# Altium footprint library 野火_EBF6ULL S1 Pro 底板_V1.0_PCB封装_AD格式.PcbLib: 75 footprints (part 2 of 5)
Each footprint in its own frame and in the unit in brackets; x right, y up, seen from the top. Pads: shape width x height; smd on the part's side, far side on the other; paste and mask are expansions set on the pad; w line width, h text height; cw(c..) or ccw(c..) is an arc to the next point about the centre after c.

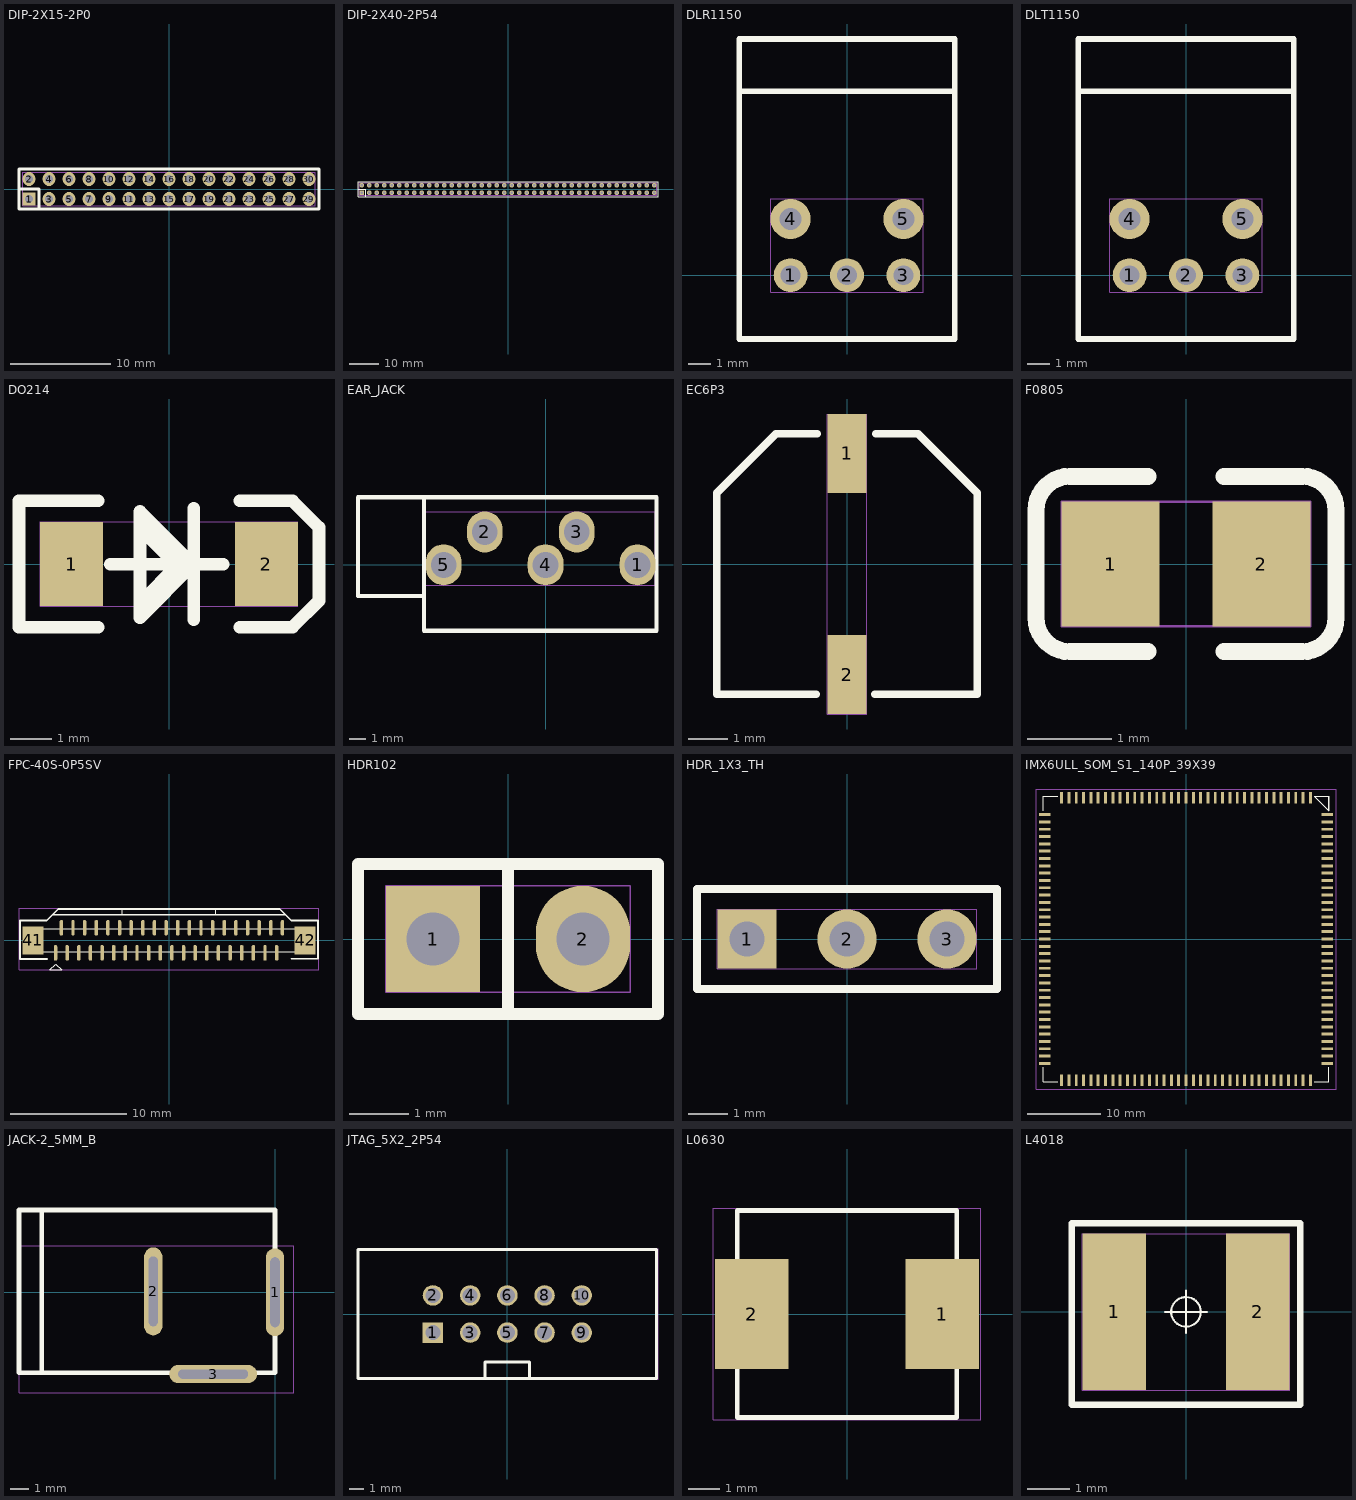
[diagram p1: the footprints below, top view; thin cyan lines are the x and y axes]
## DIP-2X15-2P0 [mil]
pads (30):
  rect 50x50 hole 32 mask+2: 1(-551.18,-39.37)
  oval 50x55 hole 32 mask+2: 2(-551.18,39.37) 3(-472.44,-39.37) 4(-472.44,39.37) 5(-393.7,-39.37) 6(-393.7,39.37) 7(-314.96,-39.37) 8(-314.96,39.37) 9(-236.22,-39.37) 10(-236.22,39.37) 11(-157.48,-39.37) 12(-157.48,39.37) 13(-78.74,-39.37) 14(-78.74,39.37) 15(0,-39.37) 16(0,39.37) 17(78.74,-39.37) 18(78.74,39.37) 19(157.48,-39.37) 20(157.48,39.37) 21(236.22,-39.37) 22(236.22,39.37) 23(314.96,-39.37) 24(314.96,39.37) 25(393.7,-39.37) 26(393.7,39.37) 27(472.44,-39.37) 28(472.44,39.37) 29(551.18,-39.37) 30(551.18,39.37)
Top Overlay:
  lines w10: -590.55,0 -511.81,0 -511.81,-78.74 ; -590.55,-78.74 590.55,-78.74 590.55,78.74 -590.55,78.74 -590.55,-78.74
Top Assembly:
  text "J38" at 57.25,25 h50
Mechanical 20:
  lines w1: -576.18,-66.87 576.18,-66.87 576.18,66.87 -576.18,66.87 -576.18,-66.87

## DIP-2X40-2P54 [mil]
pads (80):
  rect 62.99x62.99 hole 35.43 mask+2: 1(-1950,-50)
  round 62.99 hole 35.43 mask+2: 2(-1950,50) 3(-1850,-50) 4(-1850,50) 5(-1750,-50) 6(-1750,50) 7(-1650,-50) 8(-1650,50) 9(-1550,-50) 10(-1550,50) 11(-1450,-50) 12(-1450,50) 13(-1350,-50) 14(-1350,50) 15(-1250,-50) 16(-1250,50) 17(-1150,-50) 18(-1150,50) 19(-1050,-50) 20(-1050,50) 21(-950,-50) 22(-950,50) 23(-850,-50) 24(-850,50) 25(-750,-50) 26(-750,50) 27(-650,-50) 28(-650,50) 29(-550,-50) 30(-550,50) 31(-450,-50) 32(-450,50) 33(-350,-50) 34(-350,50) 35(-250,-50) 36(-250,50) 37(-150,-50) 38(-150,50) 39(-50,-50) 40(-50,50) 41(50,-50) 42(50,50) 43(150,-50) 44(150,50) 45(250,-50) 46(250,50) 47(350,-50) 48(350,50) 49(450,-50) 50(450,50) 51(550,-50) 52(550,50) 53(650,-50) 54(650,50) 55(750,-50) 56(750,50) 57(850,-50) 58(850,50) 59(950,-50) 60(950,50) 61(1050,-50) 62(1050,50) 63(1150,-50) 64(1150,50) 65(1250,-50) 66(1250,50) 67(1350,-50) 68(1350,50) 69(1450,-50) 70(1450,50) 71(1550,-50) 72(1550,50) 73(1650,-50) 74(1650,50) 75(1750,-50) 76(1750,50) 77(1850,-50) 78(1850,50) 79(1950,-50) 80(1950,50)
Top Overlay:
  lines w12: -2000,0 -1900,0 -1900,-100 ; -2000,-100 2000,-100 2000,100 -2000,100 -2000,-100
Top Assembly:
  text "CN5" at 65.11,25 h50
Mechanical 20:
  lines w1: -1981,-81 -1981,81 1981,81 1981,-81 -1981,-81

## DLR1150 [mil]
pads (5):
  round 60 hole 35 mask+2: 1(-100,0) 2(0,0) 3(100,0)
  round 70.87 hole 39.37 mask+2: 4(-100,99.61) 5(100,99.61)
Top Overlay:
  lines w10: -190.94,325.98 190.94,325.98 ; -190.94,325.98 -190.94,-112.99 190.94,-112.99 190.94,325.98 ; -190.94,325.98 -190.94,418.5 190.94,418.5 190.94,325.98
Top Assembly:
  text "CN8" at -65.11,-25 h50
Mechanical 20:
  lines w1: -135.43,-30 135.43,-30 135.43,135.04 -135.43,135.04 -135.43,-30

## DLT1150 [mil]
pads (5):
  round 60 hole 35 mask+2: 1(-100,0) 2(0,0) 3(100,0)
  round 70.87 hole 39.37 mask+2: 4(-100,99.61) 5(100,99.61)
Top Overlay:
  lines w10: -190.94,325.98 -190.94,418.5 190.94,418.5 190.94,325.98 ; -190.94,325.98 -190.94,-112.99 190.94,-112.99 190.94,325.98 ; -190.94,325.98 190.94,325.98
Top Assembly:
  text "CN12" at -83.44,-25 h50
Mechanical 20:
  lines w1: -135.43,-30 135.43,-30 135.43,135.04 -135.43,135.04 -135.43,-30

## DO214 [mil]
pads (2):
  rect 60x80 smd mask+2: 1(-92.5,0) 2(92.5,0)
Top Overlay:
  lines w1: -27.58,-25.06 -27.58,22.87 -1.5,22.87 -1.5,-25.06 -27.58,-25.06
  lines w12: -67.5,-60 -142.5,-60 -142.5,60 -67.5,60 ; -55.58,-0.13 51.42,-0.13 ; -27.58,33.87 7.79,-1.51 -25.84,-35.13 ; 23.42,-53.13 23.42,52.87 ; 67.5,-60 117.42,-60 142.5,-34.92 142.5,34.87 117.37,60 67.5,60 ; -27.58,-51.13 23.42,-0.13 23.42,-1.13 -27.58,49.87 -27.58,-51.13
Top Assembly:
  text "D2" at 38.93,25 h50
Mechanical 20:
  lines w1: -122.5,-40 122.5,-40 122.5,40 -122.5,40 -122.5,-40

## EAR_JACK [mil]
pads (5):
  oval 86x98 hole 62 mask+2: 1(220.47,0) 2(-145.67,78.74) 3(74.8,78.74) 4(0,0) 5(-244.1,0)
Top Overlay:
  lines w10: -294.49,-75.03 -449.49,-75.03 -449.49,161.97 -294.49,161.97 ; -291.49,-158.03 -291.49,161.97 265.51,161.97 265.51,-158.03 -291.49,-158.03
Top Assembly:
  text "J32" at 57.25,25 h50
Mechanical 20:
  lines w1: -287.1,-49 263.47,-49 263.47,127.74 -287.1,127.74 -287.1,-49

## EC6P3 [mm]
pads (2):
  rect 1x2 smd mask+0.051: 1(0,2.8) 2(0,-2.8)
Top Overlay:
  lines w0.2: -0.787,-3.3 -3.3,-3.3 -3.3,1.8 -1.8,3.3 -0.762,3.3 ; 0.711,-3.3 3.3,-3.3 3.3,1.8 1.8,3.3 0.737,3.3
Top Assembly:
  text "C93" at -1.621,-0.635 h1.27
Mechanical 20:
  lines w0.025: -0.5,-3.8 0.5,-3.8 0.5,3.8 -0.5,3.8 -0.5,-3.8

## F0805 [mm]
pads (2):
  rect 1.16x1.47 smd mask+0.051: 1(-0.89,0) 2(0.89,0)
Top Overlay:
  lines w0.2: -0.45,-1.035 -1.37,-1.035 cw(c-1.37,-0.635) -1.77,-0.635 -1.77,0.635 cw(c-1.37,0.635) -1.37,1.035 -0.45,1.035 ; 0.45,-1.035 1.37,-1.035 ccw(c1.37,-0.635) 1.77,-0.635 1.77,0.635 ccw(c1.37,0.635) 1.37,1.035 0.45,1.035
Top Assembly:
  text "F1" at -0.617,-0.635 h1.27
Mechanical 20:
  lines w0.025: -1.47,-0.735 1.47,-0.735 1.47,0.735 -1.47,0.735 -1.47,-0.735

## FPC-40S-0P5SV [mm]
pads (42):
  oval 0.3x1.35 smd mask+0.05: 1(-9.75,-1.076) 2(-9.25,1.076) 3(-8.75,-1.076) 4(-8.25,1.076) 5(-7.75,-1.076) 6(-7.25,1.076) 7(-6.75,-1.076) 8(-6.25,1.076) 9(-5.75,-1.076) 10(-5.25,1.076) 11(-4.75,-1.076) 12(-4.25,1.076) 13(-3.75,-1.076) 14(-3.25,1.076) 15(-2.75,-1.076) 16(-2.25,1.076) 17(-1.75,-1.076) 18(-1.25,1.076) 19(-0.75,-1.076) 20(-0.25,1.076) 21(0.25,-1.076) 22(0.75,1.076) 23(1.25,-1.076) 24(1.75,1.076) 25(2.25,-1.076) 26(2.75,1.076) 27(3.25,-1.076) 28(3.75,1.076) 29(4.25,-1.076) 30(4.75,1.076) 31(5.25,-1.076) 32(5.75,1.076) 33(6.25,-1.076) 34(6.75,1.076) 35(7.25,-1.076) 36(7.75,1.076) 37(8.25,-1.076) 38(8.75,1.076) 39(9.25,-1.076) 40(9.75,1.076)
  rect 1.8x2.4 smd mask+0.05: 41(-11.691,0) 42(11.691,0)
Top Overlay:
  lines w0.025: -11.8,-1 -11.8,1 11.8,1 11.8,-1 -11.8,-1 ; -10.254,-2.548 -9.746,-2.04 -9.238,-2.548 -10.254,-2.548 ; -4,2.208 4,2.208 4,2.708 -4,2.708 -4,2.208
  lines w0.152: -10.489,-1.597 -12.8,-1.597 -12.8,1.7 ; -10,2.2 10,2.2 ; 10.51,-1.58 12.8,-1.58 12.8,-0.9 12.8,1.7 ; -12.8,1.7 -12.8,1.701 ; -12.8,1.7 -10.5,1.7 -9.5,2.7 9.5,2.7 10.5,1.7 12.8,1.7 ; 12.8,1.7 12.8,1.701
Top Assembly:
  text "J16" at 1.324,0.635 h1.27
Mechanical 20:
  lines w0.025: -12.876,-2.548 12.876,-2.548 12.876,2.776 -12.876,2.776 -12.876,-2.548

## HDR102 [mil]
pads (2):
  rect 62.99x70.87 / inner oval 62.99x70.87 / far side rect 62.99x70.87 hole 35.43 mask+1.97: 1(-50,0)
  oval 62.99x70.87 hole 35.43 mask+1.97: 2(50,0)
Top Overlay:
  lines w8: 0,-50 0,50 ; -100,-50 100,-50 100,50 -100,50 -100,-50
Top Assembly:
  text "J30" at -57.25,-25 h50
Mechanical 20:
  lines w1: -81.5,-35.43 81.5,-35.43 81.5,35.43 -81.5,35.43 -81.5,-35.43

## HDR_1X3_TH [mil]
pads (3):
  rect 59.06x59.06 hole 35.43 mask+2: 1(-100,0)
  round 59.06 hole 35.43 mask+2: 2(0,0) 3(100,0)
Top Overlay:
  lines w7.87: -150,-50 150,-50 150,50 -150,50 -150,-50
Top Assembly:
  text "J37" at -57.25,-25 h50
Mechanical 20:
  lines w1: -129.53,-29.53 129.53,-29.53 129.53,29.53 -129.53,29.53 -129.53,-29.53

## IMX6ULL_SOM_S1_140P_39X39 [mm]
pads (140):
  rect 0.4x1.6 smd paste+0.05 mask+0.05: 1(17,19.3) 2(16,19.3) 3(15,19.3) 4(14,19.3) 5(13,19.3) 6(12,19.3) 7(11,19.3) 8(10,19.3) 9(9,19.3) 10(8,19.3) 11(7,19.3) 12(6,19.3) 13(5,19.3) 14(4,19.3) 15(3,19.3) 16(2,19.3) 17(1,19.3) 18(0,19.3) 19(-1,19.3) 20(-2,19.3) 21(-3,19.3) 22(-4,19.3) 23(-5,19.3) 24(-6,19.3) 25(-7,19.3) 26(-8,19.3) 27(-9,19.3) 28(-10,19.3) 29(-11,19.3) 30(-12,19.3) 31(-13,19.3) 32(-14,19.3) 33(-15,19.3) 34(-16,19.3) 35(-17,19.3) 71(-17,-19.3) 72(-16,-19.3) 73(-15,-19.3) 74(-14,-19.3) 75(-13,-19.3) 76(-12,-19.3) 77(-11,-19.3) 78(-10,-19.3) 79(-9,-19.3) 80(-8,-19.3) 81(-7,-19.3) 82(-6,-19.3) 83(-5,-19.3) 84(-4,-19.3) 85(-3,-19.3) 86(-2,-19.3) 87(-1,-19.3) 88(0,-19.3) 89(1,-19.3) 90(2,-19.3) 91(3,-19.3) 92(4,-19.3) 93(5,-19.3) 94(6,-19.3) 95(7,-19.3) 96(8,-19.3) 97(9,-19.3) 98(10,-19.3) 99(11,-19.3) 100(12,-19.3) 101(13,-19.3) 102(14,-19.3) 103(15,-19.3) 104(16,-19.3) 105(17,-19.3)
  rect 1.6x0.4 smd paste+0.05 mask+0.05: 36(-19.3,17) 37(-19.3,16) 38(-19.3,15) 39(-19.3,14) 40(-19.3,13) 41(-19.3,12) 42(-19.3,11) 43(-19.3,10) 44(-19.3,9) 45(-19.3,8) 46(-19.3,7) 47(-19.3,6) 48(-19.3,5) 49(-19.3,4) 50(-19.3,3) 51(-19.3,2) 52(-19.3,1) 53(-19.3,0) 54(-19.3,-1) 55(-19.3,-2) 56(-19.3,-3) 57(-19.3,-4) 58(-19.3,-5) 59(-19.3,-6) 60(-19.3,-7) 61(-19.3,-8) 62(-19.3,-9) 63(-19.3,-10) 64(-19.3,-11) 65(-19.3,-12) 66(-19.3,-13) 67(-19.3,-14) 68(-19.3,-15) 69(-19.3,-16) 70(-19.3,-17) 106(19.3,-17) 107(19.3,-16) 108(19.3,-15) 109(19.3,-14) 110(19.3,-13) 111(19.3,-12) 112(19.3,-11) 113(19.3,-10) 114(19.3,-9) 115(19.3,-8) 116(19.3,-7) 117(19.3,-6) 118(19.3,-5) 119(19.3,-4) 120(19.3,-3) 121(19.3,-2) 122(19.3,-1) 123(19.3,0) 124(19.3,1) 125(19.3,2) 126(19.3,3) 127(19.3,4) 128(19.3,5) 129(19.3,6) 130(19.3,7) 131(19.3,8) 132(19.3,9) 133(19.3,10) 134(19.3,11) 135(19.3,12) 136(19.3,13) 137(19.3,14) 138(19.3,15) 139(19.3,16) 140(19.3,17)
Top Overlay:
  lines w0.025: 17.495,19.499 19.5,19.5 19.501,17.495 17.495,19.499
  lines w0.152: -19.5,-19.5 -17.5,-19.5 -19.5,-19.5 ; -19.5,-19.5 -19.5,-17.5 -19.5,-19.5 ; -19.5,19.5 -19.5,17.5 -19.5,19.5 ; -19.5,19.5 -17.5,19.5 -19.5,19.5 ; 19.5,-19.5 17.5,-19.5 19.5,-19.5 ; 19.5,-19.5 19.5,-17.5 19.5,-19.5 ; 19.5,19.5 19.5,17.5 19.5,19.5 ; 19.5,19.5 17.5,19.5 19.5,19.5
Top Assembly:
  text "J12" at -1.355,-0.635 h1.27
Mechanical 20:
  lines w0.025: -20.5,-20.5 20.5,-20.5 20.5,20.5 -20.5,20.5 -20.5,-20.5

## JACK-2_5MM_B [mm]
pads (3):
  oval 1x4.81 / inner oval 1x4.81 / far side oval 2x4.81 hole 0.5 slot 3.81 at 90 deg mask+0.05: 1(0,0) 2(-6.659,0.046)
  oval 4.81x1 / inner oval 4.81x1 / far side oval 4.81x2 hole 0.5 slot 3.81 at 0 deg mask+0.05: 3(-3.383,-4.475)
Top Overlay:
  lines w0.254: -12.755,-4.348 -12.755,4.501 ; -14,-4.399 -14,4.501 0,4.501 0,-4.399 -14,-4.399
Top Assembly:
  text "JACK1" at -2.446,-0.635 h1.27
Mechanical 20:
  lines w0.025: -14,-5.491 1.016,-5.491 1.016,2.535 -14,2.535 -14,-5.491

## JTAG_5X2_2P54 [mil]
pads (10):
  rect 55x55 / inner round 55 / far side rect 55x55 hole 40 mask+2.5: 1(-200,-50)
  round 55 hole 40 mask+2.5: 2(-200,50) 3(-100,-50) 4(-100,50) 5(0,-50) 6(0,50) 7(100,-50) 8(100,50) 9(200,-50) 10(200,50)
Top Overlay:
  lines w8: -60,-170 -60,-130 ; -60,-129.37 60,-129.37 ; 60,-170 60,-130 ; -401.57,-173 401.57,-173 401.57,173 -401.57,173 -401.57,-173
Top Assembly:
  text "J1" at -24.29,-25 h50
Mechanical 20:
  lines w1: -400,-175 405,-175 405,175 -400,175 -400,-175

## L0630 [mm]
pads (2):
  rect 2.35x3.5 smd mask+0.05: 1(3.035,0) 2(-3.035,0)
Top Overlay:
  lines w0.15: -3.5,-3.3 -3.5,3.3 3.5,3.3 3.5,-3.3 -3.5,-3.3
Top Assembly:
  text "L12" at -1.321,-0.635 h1.27
Mechanical 20:
  lines w0.025: -4.26,-3.375 4.26,-3.375 4.26,3.375 -4.26,3.375 -4.26,-3.375

## L4018 [mm]
pads (2):
  rect 1.5x3.7 smd mask+0.05: 1(-1.7,0) 2(1.7,0)
Top Overlay:
  circle w0.05: c0,0 r0.35
  lines w0.05: -0.5,0 0.5,0 ; 0,-0.5 0,0.5
  lines w0.152: -2.7,-2.2 2.7,-2.2 2.7,2.1 -2.7,2.1 -2.7,-2.2
Top Assembly:
  text "L2" at -0.856,-0.635 h1.27
Mechanical 20:
  lines w0.025: -2.45,-1.85 2.45,-1.85 2.45,1.85 -2.45,1.85 -2.45,-1.85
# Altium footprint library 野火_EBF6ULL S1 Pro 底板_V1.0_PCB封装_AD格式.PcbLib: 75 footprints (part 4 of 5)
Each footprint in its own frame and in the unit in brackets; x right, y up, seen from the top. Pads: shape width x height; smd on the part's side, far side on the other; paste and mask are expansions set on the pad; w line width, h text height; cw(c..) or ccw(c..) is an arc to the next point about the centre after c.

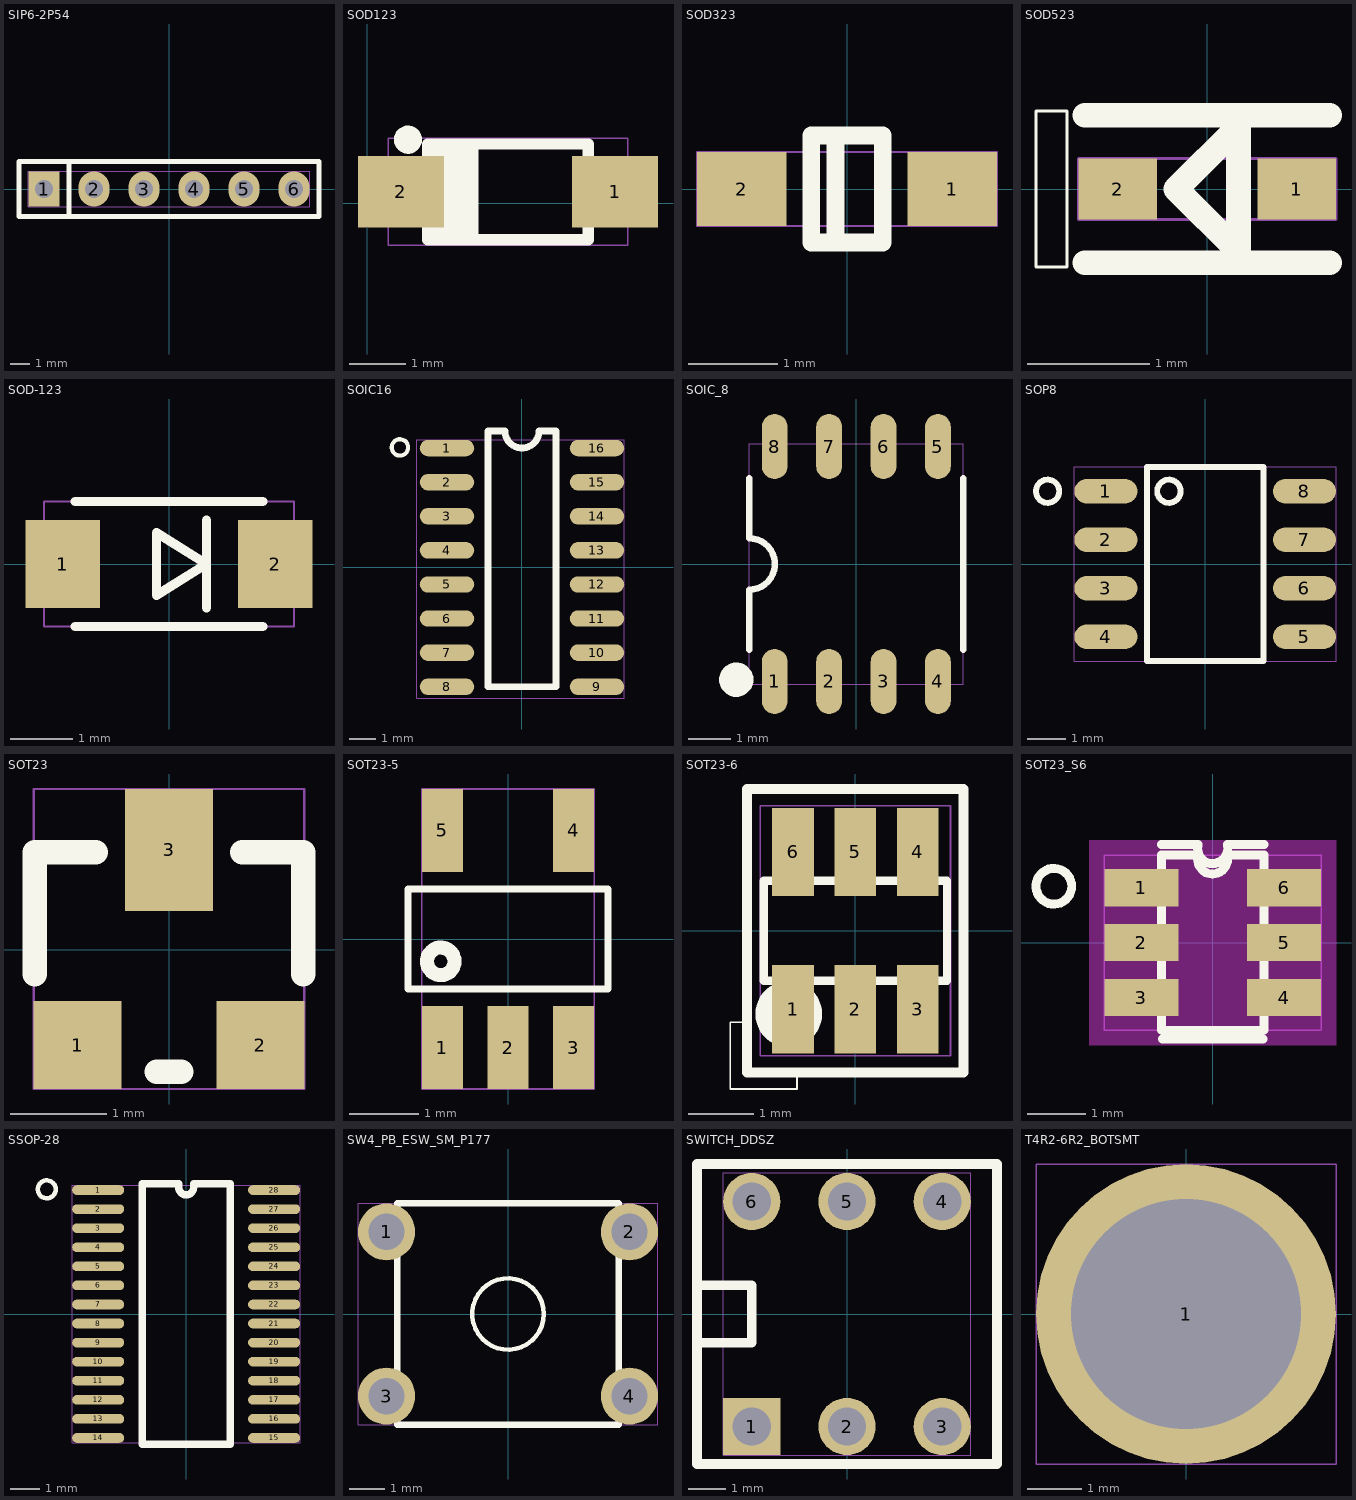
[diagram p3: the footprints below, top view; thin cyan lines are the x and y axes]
## SIP6-2P54 [mil]
pads (6):
  rect 62.99x70.87 hole 35.43 mask+1.97: 1(-250,0)
  oval 62.99x70.87 hole 35.43 mask+1.97: 2(-150,0) 3(-50,0) 4(50,0) 5(150,0) 6(250,0)
Top Overlay:
  lines w10: -200,-55.12 -200,55.12 ; -300,-55.12 -300,55.12 300,55.12 300,-55.12 -300,-55.12
Top Assembly:
  text "J15" at 53.33,25 h50
Mechanical 20:
  lines w1: -281.5,-35.43 -281.5,35.43 281.5,35.43 281.5,-35.43 -281.5,-35.43

## SOD123 [mil]
pads (2):
  rect 60x50 smd mask+5: 1(173.23,7.87) 2(23.62,7.87)
Top Overlay:
  circle w9.84: c28.54,44.29 r4.92
  lines w7.87: 46.26,-25.59 46.26,41.34 ; 50.2,-25.59 50.2,41.34 ; 54.13,-25.59 54.13,41.34 ; 58.07,-25.59 58.07,41.34 ; 62.01,-25.59 62.01,41.34 ; 65.94,-25.59 65.94,41.34 ; 73.82,-25.59 73.82,41.34 ; 42.32,-25.59 42.32,41.34 ; 42.32,-25.59 154.53,-25.59 ; 42.32,-25.59 42.32,41.34 ; 42.32,-25.59 154.53,-25.59 ; 42.32,41.34 154.53,41.34 ; 42.32,41.34 154.53,41.34 ; 154.53,-25.59 154.53,41.34 ; 154.53,-25.59 154.53,41.34 ; 22.64,-0.98 22.64,16.73 38.39,16.73 38.39,-0.98 22.64,-0.98 ; 158.46,-0.98 158.46,16.73 174.21,16.73 174.21,-0.98 158.46,-0.98
Top Assembly:
  text "D12" at 57.25,25 h50
Mechanical 20:
  lines w1: 14.76,-29.53 182.09,-29.53 182.09,45.28 14.76,45.28 14.76,-29.53

## SOD323 [mm]
pads (2):
  rect 1x0.83 smd mask+0.05: 1(1.18,0) 2(-1.18,0)
Top Overlay:
  lines w0.2: -0.13,-0.6 -0.13,0.6 ; -0.4,-0.6 0.4,-0.6 0.4,0.6 -0.4,0.6 -0.4,-0.6
Top Assembly:
  text "Z5" at 0.989,0.635 h1.27
Mechanical 20:
  lines w0.025: -1.68,-0.415 1.68,-0.415 1.68,0.415 -1.68,0.415 -1.68,-0.415

## SOD523 [mm]
pads (2):
  rect 0.64x0.5 smd mask+0.05: 1(0.73,0) 2(-0.73,0)
Top Overlay:
  lines w0.025: -1.397,-0.635 -1.143,-0.635 -1.143,0.635 -1.397,0.635 -1.397,-0.635
  lines w0.2: -1,-0.6 1,-0.6 ; -1,0.6 1,0.6
  lines w0.203: -0.254,0 0.254,-0.508 0.254,0.508 -0.254,0
Top Assembly:
  text "TVS5" at -2.053,-0.635 h1.27
Mechanical 20:
  lines w0.025: -1.05,-0.25 1.05,-0.25 1.05,0.25 -1.05,0.25 -1.05,-0.25

## SOD-123 [mil]
pads (2):
  rect 47.24x55.12 smd mask+1.97: 1(-66.93,0) 2(66.93,0)
Top Overlay:
  lines w5.91: -59.06,-39.37 59.06,-39.37 ; -59.06,39.37 59.06,39.37 ; 23.62,-27.56 23.62,27.56 ; -7.87,-19.69 23.62,0 -7.87,19.69 -7.87,-19.69
Top Assembly:
  text "D10" at -57.25,-25 h50
Mechanical 20:
  lines w1: -78.74,-39.37 78.74,-39.37 78.74,39.37 -78.74,39.37 -78.74,-39.37

## SOIC16 [mil]
pads (16):
  oval 80x24 smd mask+2.5: 1(-110,175) 2(-110,125) 3(-110,75) 4(-110,25) 5(-110,-25) 6(-110,-75) 7(-110,-125) 8(-110,-175) 9(110,-175) 10(110,-125) 11(110,-75) 12(110,-25) 13(110,25) 14(110,75) 15(110,125) 16(110,175)
Top Overlay:
  circle w5.98: c-179.02,175.99 r12.02
  lines w10: -50,-175 -50,200 -25,200 ccw(c0,200) 25,200 50,200 50,-175 -50,-175
Top Assembly:
  text "U11" at -47.85,-25 h50
Mechanical 20:
  lines w1: -154,-192 150,-192 150,187 -154,187 -154,-192

## SOIC_8 [mil]
pads (8):
  oval 23.62x59.84 smd mask+1.97: 1(-75,-107.87) 2(-25,-107.87) 3(25,-107.87) 4(75,-107.87) 5(75,107.87) 6(25,107.87) 7(-25,107.87) 8(-75,107.87)
Top Overlay:
  circle w15.75: c-110.24,-106.3 r7.88
  lines w5.91: -98.43,-23.62 ccw(c-98.43,0) -98.43,23.62 ; -98.42,-78.74 -98.42,-23.62 ; -98.42,23.62 -98.42,78.74 ; 98.42,-78.74 98.42,78.74
Top Assembly:
  text "U2" at -40.23,-25 h50
Mechanical 20:
  lines w1: -98.42,-110.24 98.42,-110.24 98.42,110.24 -98.42,110.24 -98.42,-110.24

## SOP8 [mil]
pads (8):
  oval 65x25 smd mask+1.97: 1(-102.36,75) 2(-102.36,25) 3(-102.36,-25) 4(-102.36,-75) 5(102.36,-75) 6(102.36,-25) 7(102.36,25) 8(102.36,75)
Top Overlay:
  circle w6: c-162.36,75 r12
  circle w6: c-37.36,75 r12
  lines w6: -60,-100 60,-100 60,100 -60,100 -60,-100
Top Assembly:
  text "U9" at 39.04,25 h50
Mechanical 20:
  lines w1: -134.86,-100 -134.86,100 134.86,100 134.86,-100 -134.86,-100

## SOT23 [mil]
pads (3):
  rect 36x36 smd mask+1.97: 1(-37.5,-39) 2(37.5,-39)
  rect 36x50 smd mask+1.97: 3(0,41)
Top Overlay:
  lines w10: -55,-10 -55,40 -30,40 ; -5,-50 5,-50 ; 30,40 55,40 55,-10
Top Assembly:
  text "U21" at -51.78,-25 h50
Mechanical 20:
  lines w1: -55.5,-57 55.5,-57 55.5,66 -55.5,66 -55.5,-57

## SOT23-5 [mil]
pads (5):
  rect 23.62x47.24 smd mask+1.97: 1(-37.4,-62.01) 2(0,-62.01) 3(37.4,-62.01) 4(37.4,62.01) 5(-37.4,62.01)
Top Overlay:
  circle w8: c-38.4,-12.79 r7.87
  lines w4: -57.09,-28.54 57.09,-28.54 57.09,18.7 57.09,28.54 -57.09,28.54 -57.09,18.7 -57.09,-28.54
Top Assembly:
  text "U3" at 40.23,25 h50
Mechanical 20:
  lines w1: -49.21,-85.63 49.21,-85.63 49.21,85.63 -49.21,85.63 -49.21,-85.63

## SOT23-6 [mil]
pads (6):
  rect 25x53 smd mask+3: 1(-37.4,-47.24) 2(0,-47.24) 3(37.4,-47.24) 4(37.4,47.24) 5(0,47.24) 6(-37.4,47.24)
Top Overlay:
  circle w20: c-40,-50 r10
  lines w1: -75,-95 -35,-95 -35,-85 -65,-85 -65,-55 -75,-55 -75,-95
  lines w5: -45,-30 -45,-60 -30,-60 -30,-30 ; -45,30 -45,60 -30,60 -30,30 ; -7.5,-30 -7.5,-60 7.5,-60 7.5,-30 ; -7.5,30 -7.5,60 7.5,60 7.5,30 ; 30,-30 30,-60 45,-60 45,-30 ; 30,30 30,60 45,60 45,30 ; -55,-30 -55,30 55,30 55,-30 -55,-30
  lines w6: -65,-85 -65,85 65,85 65,-85 -65,-85
Top Assembly:
  text "U29" at -61.3,-25 h50
Mechanical 20:
  lines w1: -57.09,-75 -57.09,75 57.09,75 57.09,-75 -57.09,-75

## SOT23_S6 [mil]
pads (6):
  rect 50x25 smd mask+2: 1(-48,37) 2(-48,0) 3(-48,-37) 4(48,-37) 5(48,0) 6(48,37)
Top Layer keep-out:
  region: -83.06,-68.96 -83.06,68.98 83,68.98 83,-68.96
Top Overlay:
  circle w5.98: c-107.02,37.99 r12.02
  lines w6: -34.5,66 -10,66 ; -34,-65 34,-65 ; -10,58 ccw(c-0.21,56.22) -0.21,46.27 ccw(c-0.21,56.58) 10,58 9.79,58.27 ; -10,59 -34.5,59 -34.5,-59 34.5,-59 34.5,59 10,59 ; -10,65 ccw(c-0.21,63.22) -0.21,53.27 ccw(c-0.21,63.58) 10,65 9.79,65.27 ; 10,66 34.5,66
Top Assembly:
  text "U23" at -62.49,-25 h50
Mechanical 20:
  lines w1: -73,-58.96 -73,58.98 73,58.98 73,-58.96 -73,-58.96

## SSOP-28 [mil]
pads (28):
  oval 70x13 smd mask+2.5: 1(-118.11,166.4) 2(-118.11,140.8) 3(-118.11,115.2) 4(-118.11,89.6) 5(-118.11,64) 6(-118.11,38.4) 7(-118.11,12.8) 8(-118.11,-12.8) 9(-118.11,-38.4) 10(-118.11,-64) 11(-118.11,-89.6) 12(-118.11,-115.2) 13(-118.11,-140.8) 14(-118.11,-166.4) 15(118.11,-166.4) 16(118.11,-140.8) 17(118.11,-115.2) 18(118.11,-89.6) 19(118.11,-64) 20(118.11,-38.4) 21(118.11,-12.8) 22(118.11,12.8) 23(118.11,38.4) 24(118.11,64) 25(118.11,89.6) 26(118.11,115.2) 27(118.11,140.8) 28(118.11,166.4)
Top Overlay:
  circle w5.98: c-187.13,167.39 r12.02
  lines w10: -59.06,-175 59.06,-175 59.06,175 10,175 10,170 cw(c0,170) -10,170 -10,175 -59.06,175 -59.06,-175
Top Assembly:
  text "U17" at 58.56,25 h50
Mechanical 20:
  lines w1: -153.11,-172.9 153.11,-172.9 153.11,172.9 -153.11,172.9 -153.11,-172.9

## SW4_PB_ESW_SM_P177 [mil]
pads (4):
  round 63 hole 40 mask+2.5: 1(-133.86,90.55) 2(133.86,90.55) 3(-133.86,-90.55) 4(133.86,-90.55)
Top Overlay:
  circle w5: c0,0 r39.37
  lines w7: -122.05,-122.05 -122.05,122.05 122.05,122.05 122.05,-122.05 -122.05,-122.05
Top Assembly:
  text "SW4" at -68.92,-25 h50
Mechanical 20:
  lines w1: -165.35,-122.05 165.35,-122.05 165.35,122.05 -165.35,122.05 -165.35,-122.05

## SWITCH_DDSZ [mil]
pads (6):
  rect 60x60 / inner round 60 / far side rect 60x60 hole 40 mask+2.5: 1(-100,-118.11)
  round 60 hole 40 mask+2.5: 2(0,-118.11) 3(100,-118.11) 4(100,118.11) 5(0,118.11) 6(-100,118.11)
Top Overlay:
  lines w10: -157.48,-30 -100,-30 -100,30 -157.48,30 ; -157.48,-157.48 -157.48,157.48 157.48,157.48 157.48,-157.48 -157.48,-157.48
Top Assembly:
  text "SW6" at -66.54,-25 h50
Mechanical 20:
  lines w1: -130,-148.11 130,-148.11 130,148.11 -130,148.11 -130,-148.11

## T4R2-6R2_BOTSMT [mil]
pads (1):
  round 216.54 / inner round 216.54 / far side round 244.09 hole 166.14 mask+1.97: 1(0,0)
Top Assembly:
  text "H9" at -39.04,-25 h50
Mechanical 20:
  lines w1: -108.27,-108.27 108.27,-108.27 108.27,108.27 -108.27,108.27 -108.27,-108.27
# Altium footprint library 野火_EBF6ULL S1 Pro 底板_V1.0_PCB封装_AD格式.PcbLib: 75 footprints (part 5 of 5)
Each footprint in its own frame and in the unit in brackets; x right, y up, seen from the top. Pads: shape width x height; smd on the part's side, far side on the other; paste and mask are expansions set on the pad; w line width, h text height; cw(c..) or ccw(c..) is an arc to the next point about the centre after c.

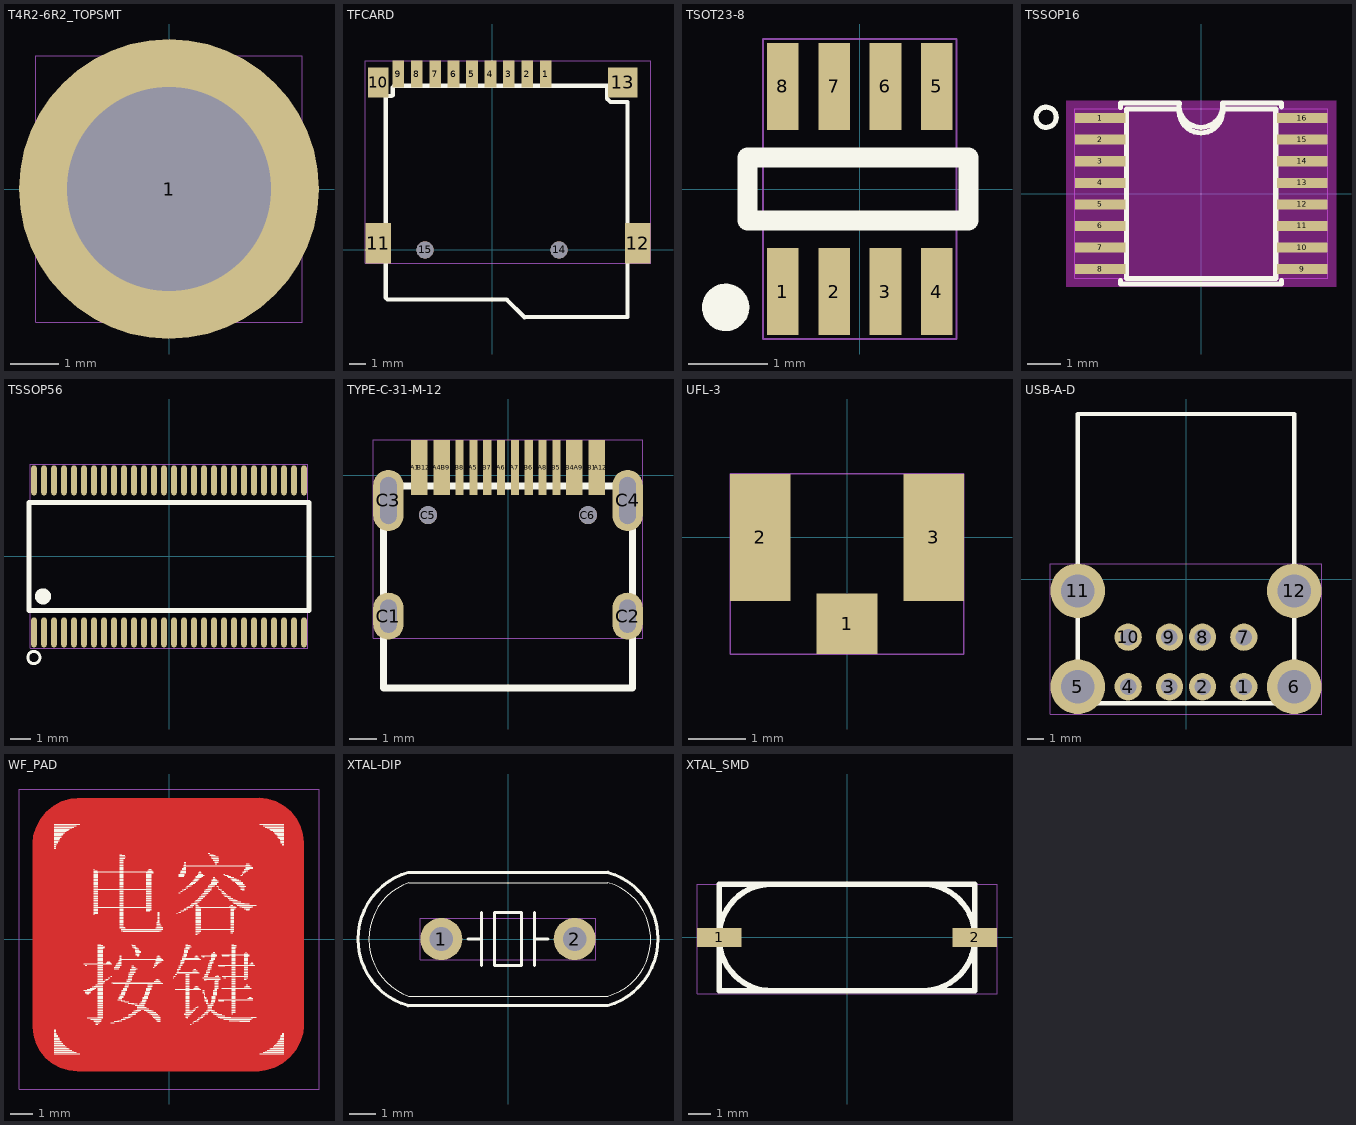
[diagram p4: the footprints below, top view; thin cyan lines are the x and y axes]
## T4R2-6R2_TOPSMT [mil]
pads (1):
  round 244.09 / inner round 216.54 / far side round 216.54 hole 166.14 mask+1.97: 1(0,0)
Top Assembly:
  text "H8" at -40.23,-25 h50
Mechanical 20:
  lines w1: -108.27,-108.27 108.27,-108.27 108.27,108.27 -108.27,108.27 -108.27,-108.27

## TFCARD [mil]
pads (15):
  rect 27.56x62.99 smd mask+1.97: 1(125.98,413.39) 2(82.67,413.39) 3(39.37,413.39) 4(-3.94,413.39) 5(-47.25,413.39) 6(-90.55,413.39) 7(-133.86,413.39) 8(-177.17,413.39) 9(-220.48,413.39)
  rect 47.24x70 smd mask+1.97: 10(-267.72,393.7)
  rect 60x95 smd mask+1.97: 11(-267.72,15.75) 12(342.52,15.75)
  rect 70x70 smd mask+1.97: 13(307.08,393.7)
  round 40 hole 40 unplated mask+2.5: 14(157.48,0) 15(-157.48,0)
Top Overlay:
  lines w10: -251.72,361.75 -235.72,361.75 -233.72,363.75 -233.72,381.75 -229.72,385.75 270.28,385.75 270.28,355.75 278.28,347.75 318.28,347.75 318.28,-157.48 76.28,-158.25 34.28,-116.25 -245.72,-116.25 -249.72,-112.25 -249.72,359.75 -251.72,361.75
Top Assembly:
  text "J22" at -57.25,-25 h50
Mechanical 20:
  lines w1: -297.72,-31.75 372.52,-31.75 372.52,444.88 -297.72,444.88 -297.72,-31.75

## TSOT23-8 [mil]
pads (8):
  rect 15.75x43.31 smd mask+2: 1(-38.39,-51.18) 2(-12.8,-51.18) 3(12.8,-51.18) 4(38.39,-51.18) 5(38.39,51.18) 6(12.8,51.18) 7(-12.8,51.18) 8(-38.39,51.18)
Top Overlay:
  circle w11.81: c-66.93,-59.06 r5.91
  lines w10: -56.1,-15.75 -56.1,15.75 54.13,15.75 54.13,-15.75 -56.1,-15.75
Top Assembly:
  text "U25" at 62.49,25 h50
Mechanical 20:
  lines w1: -48.26,-74.83 48.26,-74.83 48.26,74.83 -48.26,74.83 -48.26,-74.83

## TSSOP16 [mil]
pads (16):
  rect 60x12 smd mask+2: 1(-120,89.6) 2(-120,64) 3(-120,38.4) 4(-120,12.8) 5(-120,-12.8) 6(-120,-38.4) 7(-120,-64) 8(-120,-89.6) 9(120,-89.6) 10(120,-64) 11(120,-38.4) 12(120,-12.8) 13(120,12.8) 14(120,38.4) 15(120,64) 16(120,89.6)
Top Layer keep-out:
  region: -160,-110.5 -160,110.5 160,110.5 160,-110.5
Top Overlay:
  circle w5.98: c-184.02,90.59 r12.02
  lines w6: -95.5,-103 -95.5,-107.5 95.5,-107.5 95.5,-103 ; -95.5,102.5 -95.5,107.5 -26.25,107.5 ; -26,100.5 ccw(c-0.25,97.88) 25.5,100.5 88.5,100.5 88.5,-100.5 -88.5,-100.5 -88.5,100.5 -25.5,100.5 ; -26,107.52 ccw(c-0.25,104.63) 25.5,107.47 ; 25.5,107.5 95.5,107.5 95.5,103
Top Assembly:
  text "U24" at 63.68,25 h50
Mechanical 20:
  lines w1: -150,-100.5 150,-100.5 150,100.5 -150,100.5 -150,-100.5

## TSSOP56 [mil]
pads (56):
  oval 11.02x59.06 smd mask+2: 1(-265.75,-149.61) 2(-246.06,-149.61) 3(-226.38,-149.61) 4(-206.69,-149.61) 5(-187.01,-149.61) 6(-167.32,-149.61) 7(-147.64,-149.61) 8(-127.95,-149.61) 9(-108.27,-149.61) 10(-88.58,-149.61) 11(-68.9,-149.61) 12(-49.21,-149.61) 13(-29.53,-149.61) 14(-9.84,-149.61) 15(9.84,-149.61) 16(29.53,-149.61) 17(49.21,-149.61) 18(68.9,-149.61) 19(88.58,-149.61) 20(108.27,-149.61) 21(127.95,-149.61) 22(147.64,-149.61) 23(167.32,-149.61) 24(187.01,-149.61) 25(206.69,-149.61) 26(226.38,-149.61) 27(246.06,-149.61) 28(265.75,-149.61) 29(265.75,149.61) 30(246.06,149.61) 31(226.38,149.61) 32(206.69,149.61) 33(187.01,149.61) 34(167.32,149.61) 35(147.64,149.61) 36(127.95,149.61) 37(108.27,149.61) 38(88.58,149.61) 39(68.9,149.61) 40(49.21,149.61) 41(29.53,149.61) 42(9.84,149.61) 43(-9.84,149.61) 44(-29.53,149.61) 45(-49.21,149.61) 46(-68.9,149.61) 47(-88.58,149.61) 48(-108.27,149.61) 49(-127.95,149.61) 50(-147.64,149.61) 51(-167.32,149.61) 52(-187.01,149.61) 53(-206.69,149.61) 54(-226.38,149.61) 55(-246.06,149.61) 56(-265.75,149.61)
Top Overlay:
  circle w5.98: c-266.02,-199.01 r12.02
  circle w15.75: c-248.03,-78.74 r7.87
  lines w10: -275.59,-106.3 275.59,-106.3 275.59,106.3 -275.59,106.3 -275.59,-106.3
Top Assembly:
  text "U19" at 57.37,25 h50
Mechanical 20:
  lines w1: -273.26,-181.13 273.26,-181.13 273.26,181.13 -273.26,181.13 -273.26,-181.13

## TYPE-C-31-M-12 [mm]
pads (22):
  rect 0.3x2 smd mask+0.05: A1(-3.35,0.275) A4(-2.55,0.275) A5(-1.25,0.275) A6(-0.25,0.275) A7(0.25,0.275) A8(1.25,0.275) A9(2.55,0.275) A12(3.35,0.275) B1(3.05,0.275) B4(2.25,0.275) B5(1.75,0.275) B6(0.75,0.275) B7(-0.75,0.275) B8(-1.75,0.275) B9(-2.25,0.275) B12(-3.05,0.275)
  oval 1.1x1.7 hole 0.6 slot 1.2 at 90 deg mask+0.05: C1(-4.32,-5.095) C2(4.32,-5.095)
  oval 1.1x2.2 hole 0.6 slot 1.7 at 90 deg mask+0.05: C3(-4.32,-0.915) C4(4.32,-0.915)
  round 0.65 hole 0.65 unplated mask+0.05: C5(-2.89,-1.445) C6(2.89,-1.445)
Top Overlay:
  lines w0.254: -4.5,-7.695 -4.5,-0.395 4.5,-0.395 4.5,-7.695 -4.5,-7.695
Top Assembly:
  text "J9" at 0.859,0.635 h1.27
Mechanical 20:
  lines w0.025: -4.87,-5.895 4.87,-5.895 4.87,1.275 -4.87,1.275 -4.87,-5.895

## UFL-3 [mil]
pads (3):
  rect 41.34x41.34 smd mask+1.97: 1(0,-59.06)
  rect 41.34x86.61 smd mask+1.97: 2(-59.06,0) 3(59.06,0)
Top Assembly:
  text "CN7" at 65.11,25 h50
Mechanical 20:
  lines w1: -79.72,-79.72 79.72,-79.72 79.72,43.31 -79.72,43.31 -79.72,-79.72

## USB-A-D [mil]
pads (12):
  round 65 hole 39.37 mask+2.5: 1(137.8,-255.91) 2(39.37,-255.91) 3(-39.37,-255.91) 4(-137.8,-255.91) 7(137.8,-137.8) 8(39.37,-137.8) 9(-39.37,-137.8) 10(-137.8,-137.8)
  round 129.92 hole 78.74 mask+2: 5(-257.87,-255.91) 6(257.87,-255.91) 11(-257.87,-27.56) 12(257.87,-27.56)
Top Overlay:
  lines w10: -257.87,-295.28 257.87,-295.28 257.87,393.7 -257.87,393.7 -257.87,-295.28
Top Assembly:
  text "J36" at 56.06,25 h50
Mechanical 20:
  lines w1: -322.83,-320.87 322.83,-320.87 322.83,37.4 -322.83,37.4 -322.83,-320.87

## WF_PAD [mil]
Top Layer:
  region: -241.25,170.89 -240.1,182.59 -235.33,198.34 -227.57,212.85 -217.13,225.57 -204.41,236.01 -189.9,243.77 -174.15,248.54 -162.45,249.69 -162.44,249.62 159.77,249.89 174.19,248.47 189.27,243.9 203.17,236.47 215.35,226.47 225.35,214.29 232.78,200.39 237.35,185.31 238.77,170.89 238.5,170.88 238.54,-155.19 237.47,-166.03 232.63,-181.99 224.76,-196.7 214.18,-209.6 201.28,-220.18 186.57,-228.05 170.61,-232.89 159.77,-233.96 159.76,-233.92 -162.37,-234.28 -177.6,-232.78 -192.51,-228.25 -206.25,-220.91 -218.29,-211.03 -228.17,-198.99 -235.51,-185.25 -240.04,-170.34 -241.52,-155.25 -241.18,-155.18 -241.18,170.88
Top Overlay:
  drawing of 867 lines, arcs and shapes, not listed
Top Assembly:
  text "TPAD1" at -94.98,-25 h50
Mechanical 20:
  lines w1: -265.75,-265.75 265.75,-265.75 265.75,265.75 -265.75,265.75 -265.75,-265.75

## XTAL-DIP [mil]
pads (2):
  round 62.99 hole 35.43 mask+2: 1(-100,0) 2(100,0)
Top Overlay:
  lines w1: 149.45,-85.69 ccw(c125.85,-0.59) 149.6,84.47 ; 149.53,-85.67 -148.7,-85.67 cw(c-118.91,-0.59) -148.7,84.49 149.53,84.49
  lines w4.72: -150.08,99.98 ccw(c-120.85,0) -149.91,-100.03 ; -150,-100 150,-100 ; -150,100 150,100 ; -60,0 -40,0 ; -40,-40 -40,40 ; 40,-40 40,40 ; 40,0 60,0 ; 149.91,100.03 cw(c120.85,0) 150.08,-99.98 ; -20,-40 -20,40 20,40 20,-40 -20,-40
Top Assembly:
  text "Y6" at 37.73,25 h50
Mechanical 20:
  lines w1: -131.5,-31.5 131.5,-31.5 131.5,31.5 -131.5,31.5 -131.5,-31.5

## XTAL_SMD [mm]
pads (2):
  rect 2x0.85 smd mask+0.05: 1(-5.75,0) 2(5.75,0)
Top Overlay:
  lines w0.254: -5.75,-0.069 -5.75,0 ; -5.75,-0.068 ccw(c-3.385,-0.035) -3.352,-2.4 ; -5.75,0.002 cw(c-3.385,0.035) -3.418,2.4 ; 3.352,2.4 cw(c3.385,0.035) 5.75,0.068 ; 3.418,-2.4 ccw(c3.385,-0.035) 5.75,-0.002 ; 5.75,0 5.75,0.069 ; -5.75,-2.4 -5.75,2.4 5.75,2.4 5.75,-2.4 -5.75,-2.4
Top Assembly:
  text "Y5" at 0.989,0.635 h1.27
Mechanical 20:
  lines w0.025: -6.75,-2.54 -6.75,2.4 6.75,2.4 6.75,-2.54 -6.75,-2.54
